VERSION 5.7 ;
BUSBITCHARS "[]" ;
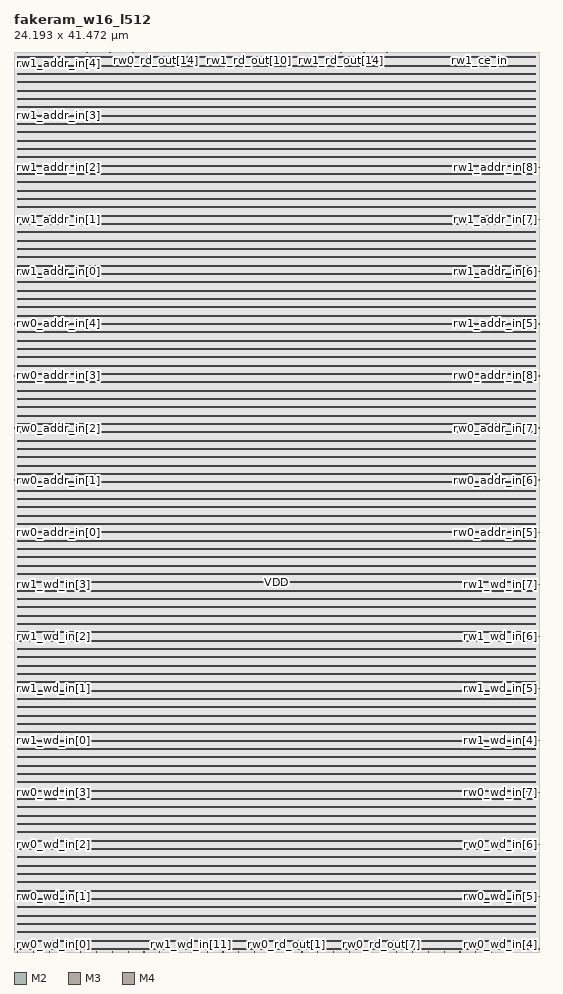
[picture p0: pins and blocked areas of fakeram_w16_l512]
MACRO fakeram_w16_l512
  FOREIGN fakeram_w16_l512 0 0 ;
  SYMMETRY X Y R90 ;
  SIZE 24.193 BY 41.472 ;
  CLASS BLOCK ;
  PIN rw0_wd_in[0]
    DIRECTION INPUT ;
    USE SIGNAL ;
    SHAPE ABUTMENT ;
    PORT
      LAYER M2 ;
      RECT 0.000 0.138 0.036 0.150 ;
    END
  END rw0_wd_in[0]
  PIN rw0_wd_in[1]
    DIRECTION INPUT ;
    USE SIGNAL ;
    SHAPE ABUTMENT ;
    PORT
      LAYER M2 ;
      RECT 0.000 2.538 0.036 2.550 ;
    END
  END rw0_wd_in[1]
  PIN rw0_wd_in[2]
    DIRECTION INPUT ;
    USE SIGNAL ;
    SHAPE ABUTMENT ;
    PORT
      LAYER M2 ;
      RECT 0.000 4.938 0.036 4.950 ;
    END
  END rw0_wd_in[2]
  PIN rw0_wd_in[3]
    DIRECTION INPUT ;
    USE SIGNAL ;
    SHAPE ABUTMENT ;
    PORT
      LAYER M2 ;
      RECT 0.000 7.338 0.036 7.350 ;
    END
  END rw0_wd_in[3]
  PIN rw0_wd_in[4]
    DIRECTION INPUT ;
    USE SIGNAL ;
    SHAPE ABUTMENT ;
    PORT
      LAYER M2 ;
      RECT 24.157 0.138 24.193 0.150 ;
    END
  END rw0_wd_in[4]
  PIN rw0_wd_in[5]
    DIRECTION INPUT ;
    USE SIGNAL ;
    SHAPE ABUTMENT ;
    PORT
      LAYER M2 ;
      RECT 24.157 2.538 24.193 2.550 ;
    END
  END rw0_wd_in[5]
  PIN rw0_wd_in[6]
    DIRECTION INPUT ;
    USE SIGNAL ;
    SHAPE ABUTMENT ;
    PORT
      LAYER M2 ;
      RECT 24.157 4.938 24.193 4.950 ;
    END
  END rw0_wd_in[6]
  PIN rw0_wd_in[7]
    DIRECTION INPUT ;
    USE SIGNAL ;
    SHAPE ABUTMENT ;
    PORT
      LAYER M2 ;
      RECT 24.157 7.338 24.193 7.350 ;
    END
  END rw0_wd_in[7]
  PIN rw0_wd_in[8]
    DIRECTION INPUT ;
    USE SIGNAL ;
    SHAPE ABUTMENT ;
    PORT
      LAYER M3 ;
      RECT 0.161 0.000 0.175 0.042 ;
    END
  END rw0_wd_in[8]
  PIN rw0_wd_in[9]
    DIRECTION INPUT ;
    USE SIGNAL ;
    SHAPE ABUTMENT ;
    PORT
      LAYER M3 ;
      RECT 0.889 0.000 0.903 0.042 ;
    END
  END rw0_wd_in[9]
  PIN rw0_wd_in[10]
    DIRECTION INPUT ;
    USE SIGNAL ;
    SHAPE ABUTMENT ;
    PORT
      LAYER M3 ;
      RECT 1.617 0.000 1.631 0.042 ;
    END
  END rw0_wd_in[10]
  PIN rw0_wd_in[11]
    DIRECTION INPUT ;
    USE SIGNAL ;
    SHAPE ABUTMENT ;
    PORT
      LAYER M3 ;
      RECT 2.345 0.000 2.359 0.042 ;
    END
  END rw0_wd_in[11]
  PIN rw0_wd_in[12]
    DIRECTION INPUT ;
    USE SIGNAL ;
    SHAPE ABUTMENT ;
    PORT
      LAYER M3 ;
      RECT 3.073 0.000 3.087 0.042 ;
    END
  END rw0_wd_in[12]
  PIN rw0_wd_in[13]
    DIRECTION INPUT ;
    USE SIGNAL ;
    SHAPE ABUTMENT ;
    PORT
      LAYER M3 ;
      RECT 3.801 0.000 3.815 0.042 ;
    END
  END rw0_wd_in[13]
  PIN rw0_wd_in[14]
    DIRECTION INPUT ;
    USE SIGNAL ;
    SHAPE ABUTMENT ;
    PORT
      LAYER M3 ;
      RECT 4.529 0.000 4.543 0.042 ;
    END
  END rw0_wd_in[14]
  PIN rw0_wd_in[15]
    DIRECTION INPUT ;
    USE SIGNAL ;
    SHAPE ABUTMENT ;
    PORT
      LAYER M3 ;
      RECT 5.257 0.000 5.271 0.042 ;
    END
  END rw0_wd_in[15]
  PIN rw1_wd_in[0]
    DIRECTION INPUT ;
    USE SIGNAL ;
    SHAPE ABUTMENT ;
    PORT
      LAYER M2 ;
      RECT 0.000 9.738 0.036 9.750 ;
    END
  END rw1_wd_in[0]
  PIN rw1_wd_in[1]
    DIRECTION INPUT ;
    USE SIGNAL ;
    SHAPE ABUTMENT ;
    PORT
      LAYER M2 ;
      RECT 0.000 12.138 0.036 12.150 ;
    END
  END rw1_wd_in[1]
  PIN rw1_wd_in[2]
    DIRECTION INPUT ;
    USE SIGNAL ;
    SHAPE ABUTMENT ;
    PORT
      LAYER M2 ;
      RECT 0.000 14.538 0.036 14.550 ;
    END
  END rw1_wd_in[2]
  PIN rw1_wd_in[3]
    DIRECTION INPUT ;
    USE SIGNAL ;
    SHAPE ABUTMENT ;
    PORT
      LAYER M2 ;
      RECT 0.000 16.938 0.036 16.950 ;
    END
  END rw1_wd_in[3]
  PIN rw1_wd_in[4]
    DIRECTION INPUT ;
    USE SIGNAL ;
    SHAPE ABUTMENT ;
    PORT
      LAYER M2 ;
      RECT 24.157 9.738 24.193 9.750 ;
    END
  END rw1_wd_in[4]
  PIN rw1_wd_in[5]
    DIRECTION INPUT ;
    USE SIGNAL ;
    SHAPE ABUTMENT ;
    PORT
      LAYER M2 ;
      RECT 24.157 12.138 24.193 12.150 ;
    END
  END rw1_wd_in[5]
  PIN rw1_wd_in[6]
    DIRECTION INPUT ;
    USE SIGNAL ;
    SHAPE ABUTMENT ;
    PORT
      LAYER M2 ;
      RECT 24.157 14.538 24.193 14.550 ;
    END
  END rw1_wd_in[6]
  PIN rw1_wd_in[7]
    DIRECTION INPUT ;
    USE SIGNAL ;
    SHAPE ABUTMENT ;
    PORT
      LAYER M2 ;
      RECT 24.157 16.938 24.193 16.950 ;
    END
  END rw1_wd_in[7]
  PIN rw1_wd_in[8]
    DIRECTION INPUT ;
    USE SIGNAL ;
    SHAPE ABUTMENT ;
    PORT
      LAYER M3 ;
      RECT 5.985 0.000 5.999 0.042 ;
    END
  END rw1_wd_in[8]
  PIN rw1_wd_in[9]
    DIRECTION INPUT ;
    USE SIGNAL ;
    SHAPE ABUTMENT ;
    PORT
      LAYER M3 ;
      RECT 6.713 0.000 6.727 0.042 ;
    END
  END rw1_wd_in[9]
  PIN rw1_wd_in[10]
    DIRECTION INPUT ;
    USE SIGNAL ;
    SHAPE ABUTMENT ;
    PORT
      LAYER M3 ;
      RECT 7.441 0.000 7.455 0.042 ;
    END
  END rw1_wd_in[10]
  PIN rw1_wd_in[11]
    DIRECTION INPUT ;
    USE SIGNAL ;
    SHAPE ABUTMENT ;
    PORT
      LAYER M3 ;
      RECT 8.169 0.000 8.183 0.042 ;
    END
  END rw1_wd_in[11]
  PIN rw1_wd_in[12]
    DIRECTION INPUT ;
    USE SIGNAL ;
    SHAPE ABUTMENT ;
    PORT
      LAYER M3 ;
      RECT 8.897 0.000 8.911 0.042 ;
    END
  END rw1_wd_in[12]
  PIN rw1_wd_in[13]
    DIRECTION INPUT ;
    USE SIGNAL ;
    SHAPE ABUTMENT ;
    PORT
      LAYER M3 ;
      RECT 9.625 0.000 9.639 0.042 ;
    END
  END rw1_wd_in[13]
  PIN rw1_wd_in[14]
    DIRECTION INPUT ;
    USE SIGNAL ;
    SHAPE ABUTMENT ;
    PORT
      LAYER M3 ;
      RECT 10.353 0.000 10.367 0.042 ;
    END
  END rw1_wd_in[14]
  PIN rw1_wd_in[15]
    DIRECTION INPUT ;
    USE SIGNAL ;
    SHAPE ABUTMENT ;
    PORT
      LAYER M3 ;
      RECT 11.081 0.000 11.095 0.042 ;
    END
  END rw1_wd_in[15]
  PIN rw0_rd_out[0]
    DIRECTION OUTPUT ;
    USE SIGNAL ;
    SHAPE ABUTMENT ;
    PORT
      LAYER M3 ;
      RECT 11.809 0.000 11.823 0.042 ;
    END
  END rw0_rd_out[0]
  PIN rw0_rd_out[1]
    DIRECTION OUTPUT ;
    USE SIGNAL ;
    SHAPE ABUTMENT ;
    PORT
      LAYER M3 ;
      RECT 12.537 0.000 12.551 0.042 ;
    END
  END rw0_rd_out[1]
  PIN rw0_rd_out[2]
    DIRECTION OUTPUT ;
    USE SIGNAL ;
    SHAPE ABUTMENT ;
    PORT
      LAYER M3 ;
      RECT 13.265 0.000 13.279 0.042 ;
    END
  END rw0_rd_out[2]
  PIN rw0_rd_out[3]
    DIRECTION OUTPUT ;
    USE SIGNAL ;
    SHAPE ABUTMENT ;
    PORT
      LAYER M3 ;
      RECT 13.993 0.000 14.007 0.042 ;
    END
  END rw0_rd_out[3]
  PIN rw0_rd_out[4]
    DIRECTION OUTPUT ;
    USE SIGNAL ;
    SHAPE ABUTMENT ;
    PORT
      LAYER M3 ;
      RECT 14.721 0.000 14.735 0.042 ;
    END
  END rw0_rd_out[4]
  PIN rw0_rd_out[5]
    DIRECTION OUTPUT ;
    USE SIGNAL ;
    SHAPE ABUTMENT ;
    PORT
      LAYER M3 ;
      RECT 15.449 0.000 15.463 0.042 ;
    END
  END rw0_rd_out[5]
  PIN rw0_rd_out[6]
    DIRECTION OUTPUT ;
    USE SIGNAL ;
    SHAPE ABUTMENT ;
    PORT
      LAYER M3 ;
      RECT 16.177 0.000 16.191 0.042 ;
    END
  END rw0_rd_out[6]
  PIN rw0_rd_out[7]
    DIRECTION OUTPUT ;
    USE SIGNAL ;
    SHAPE ABUTMENT ;
    PORT
      LAYER M3 ;
      RECT 16.905 0.000 16.919 0.042 ;
    END
  END rw0_rd_out[7]
  PIN rw0_rd_out[8]
    DIRECTION OUTPUT ;
    USE SIGNAL ;
    SHAPE ABUTMENT ;
    PORT
      LAYER M3 ;
      RECT 0.161 41.430 0.175 41.472 ;
    END
  END rw0_rd_out[8]
  PIN rw0_rd_out[9]
    DIRECTION OUTPUT ;
    USE SIGNAL ;
    SHAPE ABUTMENT ;
    PORT
      LAYER M3 ;
      RECT 1.225 41.430 1.239 41.472 ;
    END
  END rw0_rd_out[9]
  PIN rw0_rd_out[10]
    DIRECTION OUTPUT ;
    USE SIGNAL ;
    SHAPE ABUTMENT ;
    PORT
      LAYER M3 ;
      RECT 2.289 41.430 2.303 41.472 ;
    END
  END rw0_rd_out[10]
  PIN rw0_rd_out[11]
    DIRECTION OUTPUT ;
    USE SIGNAL ;
    SHAPE ABUTMENT ;
    PORT
      LAYER M3 ;
      RECT 3.353 41.430 3.367 41.472 ;
    END
  END rw0_rd_out[11]
  PIN rw0_rd_out[12]
    DIRECTION OUTPUT ;
    USE SIGNAL ;
    SHAPE ABUTMENT ;
    PORT
      LAYER M3 ;
      RECT 4.417 41.430 4.431 41.472 ;
    END
  END rw0_rd_out[12]
  PIN rw0_rd_out[13]
    DIRECTION OUTPUT ;
    USE SIGNAL ;
    SHAPE ABUTMENT ;
    PORT
      LAYER M3 ;
      RECT 5.481 41.430 5.495 41.472 ;
    END
  END rw0_rd_out[13]
  PIN rw0_rd_out[14]
    DIRECTION OUTPUT ;
    USE SIGNAL ;
    SHAPE ABUTMENT ;
    PORT
      LAYER M3 ;
      RECT 6.545 41.430 6.559 41.472 ;
    END
  END rw0_rd_out[14]
  PIN rw0_rd_out[15]
    DIRECTION OUTPUT ;
    USE SIGNAL ;
    SHAPE ABUTMENT ;
    PORT
      LAYER M3 ;
      RECT 7.609 41.430 7.623 41.472 ;
    END
  END rw0_rd_out[15]
  PIN rw1_rd_out[0]
    DIRECTION OUTPUT ;
    USE SIGNAL ;
    SHAPE ABUTMENT ;
    PORT
      LAYER M3 ;
      RECT 17.633 0.000 17.647 0.042 ;
    END
  END rw1_rd_out[0]
  PIN rw1_rd_out[1]
    DIRECTION OUTPUT ;
    USE SIGNAL ;
    SHAPE ABUTMENT ;
    PORT
      LAYER M3 ;
      RECT 18.361 0.000 18.375 0.042 ;
    END
  END rw1_rd_out[1]
  PIN rw1_rd_out[2]
    DIRECTION OUTPUT ;
    USE SIGNAL ;
    SHAPE ABUTMENT ;
    PORT
      LAYER M3 ;
      RECT 19.089 0.000 19.103 0.042 ;
    END
  END rw1_rd_out[2]
  PIN rw1_rd_out[3]
    DIRECTION OUTPUT ;
    USE SIGNAL ;
    SHAPE ABUTMENT ;
    PORT
      LAYER M3 ;
      RECT 19.817 0.000 19.831 0.042 ;
    END
  END rw1_rd_out[3]
  PIN rw1_rd_out[4]
    DIRECTION OUTPUT ;
    USE SIGNAL ;
    SHAPE ABUTMENT ;
    PORT
      LAYER M3 ;
      RECT 20.545 0.000 20.559 0.042 ;
    END
  END rw1_rd_out[4]
  PIN rw1_rd_out[5]
    DIRECTION OUTPUT ;
    USE SIGNAL ;
    SHAPE ABUTMENT ;
    PORT
      LAYER M3 ;
      RECT 21.273 0.000 21.287 0.042 ;
    END
  END rw1_rd_out[5]
  PIN rw1_rd_out[6]
    DIRECTION OUTPUT ;
    USE SIGNAL ;
    SHAPE ABUTMENT ;
    PORT
      LAYER M3 ;
      RECT 22.001 0.000 22.015 0.042 ;
    END
  END rw1_rd_out[6]
  PIN rw1_rd_out[7]
    DIRECTION OUTPUT ;
    USE SIGNAL ;
    SHAPE ABUTMENT ;
    PORT
      LAYER M3 ;
      RECT 22.729 0.000 22.743 0.042 ;
    END
  END rw1_rd_out[7]
  PIN rw1_rd_out[8]
    DIRECTION OUTPUT ;
    USE SIGNAL ;
    SHAPE ABUTMENT ;
    PORT
      LAYER M3 ;
      RECT 8.673 41.430 8.687 41.472 ;
    END
  END rw1_rd_out[8]
  PIN rw1_rd_out[9]
    DIRECTION OUTPUT ;
    USE SIGNAL ;
    SHAPE ABUTMENT ;
    PORT
      LAYER M3 ;
      RECT 9.737 41.430 9.751 41.472 ;
    END
  END rw1_rd_out[9]
  PIN rw1_rd_out[10]
    DIRECTION OUTPUT ;
    USE SIGNAL ;
    SHAPE ABUTMENT ;
    PORT
      LAYER M3 ;
      RECT 10.801 41.430 10.815 41.472 ;
    END
  END rw1_rd_out[10]
  PIN rw1_rd_out[11]
    DIRECTION OUTPUT ;
    USE SIGNAL ;
    SHAPE ABUTMENT ;
    PORT
      LAYER M3 ;
      RECT 11.865 41.430 11.879 41.472 ;
    END
  END rw1_rd_out[11]
  PIN rw1_rd_out[12]
    DIRECTION OUTPUT ;
    USE SIGNAL ;
    SHAPE ABUTMENT ;
    PORT
      LAYER M3 ;
      RECT 12.929 41.430 12.943 41.472 ;
    END
  END rw1_rd_out[12]
  PIN rw1_rd_out[13]
    DIRECTION OUTPUT ;
    USE SIGNAL ;
    SHAPE ABUTMENT ;
    PORT
      LAYER M3 ;
      RECT 13.993 41.430 14.007 41.472 ;
    END
  END rw1_rd_out[13]
  PIN rw1_rd_out[14]
    DIRECTION OUTPUT ;
    USE SIGNAL ;
    SHAPE ABUTMENT ;
    PORT
      LAYER M3 ;
      RECT 15.057 41.430 15.071 41.472 ;
    END
  END rw1_rd_out[14]
  PIN rw1_rd_out[15]
    DIRECTION OUTPUT ;
    USE SIGNAL ;
    SHAPE ABUTMENT ;
    PORT
      LAYER M3 ;
      RECT 16.121 41.430 16.135 41.472 ;
    END
  END rw1_rd_out[15]
  PIN rw0_addr_in[0]
    DIRECTION INPUT ;
    USE SIGNAL ;
    SHAPE ABUTMENT ;
    PORT
      LAYER M2 ;
      RECT 0.000 19.338 0.036 19.350 ;
    END
  END rw0_addr_in[0]
  PIN rw0_addr_in[1]
    DIRECTION INPUT ;
    USE SIGNAL ;
    SHAPE ABUTMENT ;
    PORT
      LAYER M2 ;
      RECT 0.000 21.738 0.036 21.750 ;
    END
  END rw0_addr_in[1]
  PIN rw0_addr_in[2]
    DIRECTION INPUT ;
    USE SIGNAL ;
    SHAPE ABUTMENT ;
    PORT
      LAYER M2 ;
      RECT 0.000 24.138 0.036 24.150 ;
    END
  END rw0_addr_in[2]
  PIN rw0_addr_in[3]
    DIRECTION INPUT ;
    USE SIGNAL ;
    SHAPE ABUTMENT ;
    PORT
      LAYER M2 ;
      RECT 0.000 26.538 0.036 26.550 ;
    END
  END rw0_addr_in[3]
  PIN rw0_addr_in[4]
    DIRECTION INPUT ;
    USE SIGNAL ;
    SHAPE ABUTMENT ;
    PORT
      LAYER M2 ;
      RECT 0.000 28.938 0.036 28.950 ;
    END
  END rw0_addr_in[4]
  PIN rw0_addr_in[5]
    DIRECTION INPUT ;
    USE SIGNAL ;
    SHAPE ABUTMENT ;
    PORT
      LAYER M2 ;
      RECT 24.157 19.338 24.193 19.350 ;
    END
  END rw0_addr_in[5]
  PIN rw0_addr_in[6]
    DIRECTION INPUT ;
    USE SIGNAL ;
    SHAPE ABUTMENT ;
    PORT
      LAYER M2 ;
      RECT 24.157 21.738 24.193 21.750 ;
    END
  END rw0_addr_in[6]
  PIN rw0_addr_in[7]
    DIRECTION INPUT ;
    USE SIGNAL ;
    SHAPE ABUTMENT ;
    PORT
      LAYER M2 ;
      RECT 24.157 24.138 24.193 24.150 ;
    END
  END rw0_addr_in[7]
  PIN rw0_addr_in[8]
    DIRECTION INPUT ;
    USE SIGNAL ;
    SHAPE ABUTMENT ;
    PORT
      LAYER M2 ;
      RECT 24.157 26.538 24.193 26.550 ;
    END
  END rw0_addr_in[8]
  PIN rw1_addr_in[0]
    DIRECTION INPUT ;
    USE SIGNAL ;
    SHAPE ABUTMENT ;
    PORT
      LAYER M2 ;
      RECT 0.000 31.338 0.036 31.350 ;
    END
  END rw1_addr_in[0]
  PIN rw1_addr_in[1]
    DIRECTION INPUT ;
    USE SIGNAL ;
    SHAPE ABUTMENT ;
    PORT
      LAYER M2 ;
      RECT 0.000 33.738 0.036 33.750 ;
    END
  END rw1_addr_in[1]
  PIN rw1_addr_in[2]
    DIRECTION INPUT ;
    USE SIGNAL ;
    SHAPE ABUTMENT ;
    PORT
      LAYER M2 ;
      RECT 0.000 36.138 0.036 36.150 ;
    END
  END rw1_addr_in[2]
  PIN rw1_addr_in[3]
    DIRECTION INPUT ;
    USE SIGNAL ;
    SHAPE ABUTMENT ;
    PORT
      LAYER M2 ;
      RECT 0.000 38.538 0.036 38.550 ;
    END
  END rw1_addr_in[3]
  PIN rw1_addr_in[4]
    DIRECTION INPUT ;
    USE SIGNAL ;
    SHAPE ABUTMENT ;
    PORT
      LAYER M2 ;
      RECT 0.000 40.938 0.036 40.950 ;
    END
  END rw1_addr_in[4]
  PIN rw1_addr_in[5]
    DIRECTION INPUT ;
    USE SIGNAL ;
    SHAPE ABUTMENT ;
    PORT
      LAYER M2 ;
      RECT 24.157 28.938 24.193 28.950 ;
    END
  END rw1_addr_in[5]
  PIN rw1_addr_in[6]
    DIRECTION INPUT ;
    USE SIGNAL ;
    SHAPE ABUTMENT ;
    PORT
      LAYER M2 ;
      RECT 24.157 31.338 24.193 31.350 ;
    END
  END rw1_addr_in[6]
  PIN rw1_addr_in[7]
    DIRECTION INPUT ;
    USE SIGNAL ;
    SHAPE ABUTMENT ;
    PORT
      LAYER M2 ;
      RECT 24.157 33.738 24.193 33.750 ;
    END
  END rw1_addr_in[7]
  PIN rw1_addr_in[8]
    DIRECTION INPUT ;
    USE SIGNAL ;
    SHAPE ABUTMENT ;
    PORT
      LAYER M2 ;
      RECT 24.157 36.138 24.193 36.150 ;
    END
  END rw1_addr_in[8]
  PIN rw0_we_in
    DIRECTION INPUT ;
    USE SIGNAL ;
    SHAPE ABUTMENT ;
    PORT
      LAYER M3 ;
      RECT 17.185 41.430 17.199 41.472 ;
    END
  END rw0_we_in
  PIN rw0_ce_in
    DIRECTION INPUT ;
    USE SIGNAL ;
    SHAPE ABUTMENT ;
    PORT
      LAYER M3 ;
      RECT 18.249 41.430 18.263 41.472 ;
    END
  END rw0_ce_in
  PIN rw0_clk
    DIRECTION INPUT ;
    USE SIGNAL ;
    SHAPE ABUTMENT ;
    PORT
      LAYER M3 ;
      RECT 19.313 41.430 19.327 41.472 ;
    END
  END rw0_clk
  PIN rw1_we_in
    DIRECTION INPUT ;
    USE SIGNAL ;
    SHAPE ABUTMENT ;
    PORT
      LAYER M3 ;
      RECT 20.377 41.430 20.391 41.472 ;
    END
  END rw1_we_in
  PIN rw1_ce_in
    DIRECTION INPUT ;
    USE SIGNAL ;
    SHAPE ABUTMENT ;
    PORT
      LAYER M3 ;
      RECT 21.441 41.430 21.455 41.472 ;
    END
  END rw1_ce_in
  PIN rw1_clk
    DIRECTION INPUT ;
    USE SIGNAL ;
    SHAPE ABUTMENT ;
    PORT
      LAYER M3 ;
      RECT 22.505 41.430 22.519 41.472 ;
    END
  END rw1_clk
  PIN VSS
    DIRECTION INOUT ;
    USE GROUND ;
    PORT
      LAYER M4 ;
      RECT 0.168 0.120 24.025 0.168 ;
      RECT 0.168 0.504 24.025 0.552 ;
      RECT 0.168 0.888 24.025 0.936 ;
      RECT 0.168 1.272 24.025 1.320 ;
      RECT 0.168 1.656 24.025 1.704 ;
      RECT 0.168 2.040 24.025 2.088 ;
      RECT 0.168 2.424 24.025 2.472 ;
      RECT 0.168 2.808 24.025 2.856 ;
      RECT 0.168 3.192 24.025 3.240 ;
      RECT 0.168 3.576 24.025 3.624 ;
      RECT 0.168 3.960 24.025 4.008 ;
      RECT 0.168 4.344 24.025 4.392 ;
      RECT 0.168 4.728 24.025 4.776 ;
      RECT 0.168 5.112 24.025 5.160 ;
      RECT 0.168 5.496 24.025 5.544 ;
      RECT 0.168 5.880 24.025 5.928 ;
      RECT 0.168 6.264 24.025 6.312 ;
      RECT 0.168 6.648 24.025 6.696 ;
      RECT 0.168 7.032 24.025 7.080 ;
      RECT 0.168 7.416 24.025 7.464 ;
      RECT 0.168 7.800 24.025 7.848 ;
      RECT 0.168 8.184 24.025 8.232 ;
      RECT 0.168 8.568 24.025 8.616 ;
      RECT 0.168 8.952 24.025 9.000 ;
      RECT 0.168 9.336 24.025 9.384 ;
      RECT 0.168 9.720 24.025 9.768 ;
      RECT 0.168 10.104 24.025 10.152 ;
      RECT 0.168 10.488 24.025 10.536 ;
      RECT 0.168 10.872 24.025 10.920 ;
      RECT 0.168 11.256 24.025 11.304 ;
      RECT 0.168 11.640 24.025 11.688 ;
      RECT 0.168 12.024 24.025 12.072 ;
      RECT 0.168 12.408 24.025 12.456 ;
      RECT 0.168 12.792 24.025 12.840 ;
      RECT 0.168 13.176 24.025 13.224 ;
      RECT 0.168 13.560 24.025 13.608 ;
      RECT 0.168 13.944 24.025 13.992 ;
      RECT 0.168 14.328 24.025 14.376 ;
      RECT 0.168 14.712 24.025 14.760 ;
      RECT 0.168 15.096 24.025 15.144 ;
      RECT 0.168 15.480 24.025 15.528 ;
      RECT 0.168 15.864 24.025 15.912 ;
      RECT 0.168 16.248 24.025 16.296 ;
      RECT 0.168 16.632 24.025 16.680 ;
      RECT 0.168 17.016 24.025 17.064 ;
      RECT 0.168 17.400 24.025 17.448 ;
      RECT 0.168 17.784 24.025 17.832 ;
      RECT 0.168 18.168 24.025 18.216 ;
      RECT 0.168 18.552 24.025 18.600 ;
      RECT 0.168 18.936 24.025 18.984 ;
      RECT 0.168 19.320 24.025 19.368 ;
      RECT 0.168 19.704 24.025 19.752 ;
      RECT 0.168 20.088 24.025 20.136 ;
      RECT 0.168 20.472 24.025 20.520 ;
      RECT 0.168 20.856 24.025 20.904 ;
      RECT 0.168 21.240 24.025 21.288 ;
      RECT 0.168 21.624 24.025 21.672 ;
      RECT 0.168 22.008 24.025 22.056 ;
      RECT 0.168 22.392 24.025 22.440 ;
      RECT 0.168 22.776 24.025 22.824 ;
      RECT 0.168 23.160 24.025 23.208 ;
      RECT 0.168 23.544 24.025 23.592 ;
      RECT 0.168 23.928 24.025 23.976 ;
      RECT 0.168 24.312 24.025 24.360 ;
      RECT 0.168 24.696 24.025 24.744 ;
      RECT 0.168 25.080 24.025 25.128 ;
      RECT 0.168 25.464 24.025 25.512 ;
      RECT 0.168 25.848 24.025 25.896 ;
      RECT 0.168 26.232 24.025 26.280 ;
      RECT 0.168 26.616 24.025 26.664 ;
      RECT 0.168 27.000 24.025 27.048 ;
      RECT 0.168 27.384 24.025 27.432 ;
      RECT 0.168 27.768 24.025 27.816 ;
      RECT 0.168 28.152 24.025 28.200 ;
      RECT 0.168 28.536 24.025 28.584 ;
      RECT 0.168 28.920 24.025 28.968 ;
      RECT 0.168 29.304 24.025 29.352 ;
      RECT 0.168 29.688 24.025 29.736 ;
      RECT 0.168 30.072 24.025 30.120 ;
      RECT 0.168 30.456 24.025 30.504 ;
      RECT 0.168 30.840 24.025 30.888 ;
      RECT 0.168 31.224 24.025 31.272 ;
      RECT 0.168 31.608 24.025 31.656 ;
      RECT 0.168 31.992 24.025 32.040 ;
      RECT 0.168 32.376 24.025 32.424 ;
      RECT 0.168 32.760 24.025 32.808 ;
      RECT 0.168 33.144 24.025 33.192 ;
      RECT 0.168 33.528 24.025 33.576 ;
      RECT 0.168 33.912 24.025 33.960 ;
      RECT 0.168 34.296 24.025 34.344 ;
      RECT 0.168 34.680 24.025 34.728 ;
      RECT 0.168 35.064 24.025 35.112 ;
      RECT 0.168 35.448 24.025 35.496 ;
      RECT 0.168 35.832 24.025 35.880 ;
      RECT 0.168 36.216 24.025 36.264 ;
      RECT 0.168 36.600 24.025 36.648 ;
      RECT 0.168 36.984 24.025 37.032 ;
      RECT 0.168 37.368 24.025 37.416 ;
      RECT 0.168 37.752 24.025 37.800 ;
      RECT 0.168 38.136 24.025 38.184 ;
      RECT 0.168 38.520 24.025 38.568 ;
      RECT 0.168 38.904 24.025 38.952 ;
      RECT 0.168 39.288 24.025 39.336 ;
      RECT 0.168 39.672 24.025 39.720 ;
      RECT 0.168 40.056 24.025 40.104 ;
      RECT 0.168 40.440 24.025 40.488 ;
      RECT 0.168 40.824 24.025 40.872 ;
      RECT 0.168 41.208 24.025 41.256 ;
    END
  END VSS
  PIN VDD
    DIRECTION INOUT ;
    USE POWER ;
    PORT
      LAYER M4 ;
      RECT 0.168 0.120 24.025 0.168 ;
      RECT 0.168 0.504 24.025 0.552 ;
      RECT 0.168 0.888 24.025 0.936 ;
      RECT 0.168 1.272 24.025 1.320 ;
      RECT 0.168 1.656 24.025 1.704 ;
      RECT 0.168 2.040 24.025 2.088 ;
      RECT 0.168 2.424 24.025 2.472 ;
      RECT 0.168 2.808 24.025 2.856 ;
      RECT 0.168 3.192 24.025 3.240 ;
      RECT 0.168 3.576 24.025 3.624 ;
      RECT 0.168 3.960 24.025 4.008 ;
      RECT 0.168 4.344 24.025 4.392 ;
      RECT 0.168 4.728 24.025 4.776 ;
      RECT 0.168 5.112 24.025 5.160 ;
      RECT 0.168 5.496 24.025 5.544 ;
      RECT 0.168 5.880 24.025 5.928 ;
      RECT 0.168 6.264 24.025 6.312 ;
      RECT 0.168 6.648 24.025 6.696 ;
      RECT 0.168 7.032 24.025 7.080 ;
      RECT 0.168 7.416 24.025 7.464 ;
      RECT 0.168 7.800 24.025 7.848 ;
      RECT 0.168 8.184 24.025 8.232 ;
      RECT 0.168 8.568 24.025 8.616 ;
      RECT 0.168 8.952 24.025 9.000 ;
      RECT 0.168 9.336 24.025 9.384 ;
      RECT 0.168 9.720 24.025 9.768 ;
      RECT 0.168 10.104 24.025 10.152 ;
      RECT 0.168 10.488 24.025 10.536 ;
      RECT 0.168 10.872 24.025 10.920 ;
      RECT 0.168 11.256 24.025 11.304 ;
      RECT 0.168 11.640 24.025 11.688 ;
      RECT 0.168 12.024 24.025 12.072 ;
      RECT 0.168 12.408 24.025 12.456 ;
      RECT 0.168 12.792 24.025 12.840 ;
      RECT 0.168 13.176 24.025 13.224 ;
      RECT 0.168 13.560 24.025 13.608 ;
      RECT 0.168 13.944 24.025 13.992 ;
      RECT 0.168 14.328 24.025 14.376 ;
      RECT 0.168 14.712 24.025 14.760 ;
      RECT 0.168 15.096 24.025 15.144 ;
      RECT 0.168 15.480 24.025 15.528 ;
      RECT 0.168 15.864 24.025 15.912 ;
      RECT 0.168 16.248 24.025 16.296 ;
      RECT 0.168 16.632 24.025 16.680 ;
      RECT 0.168 17.016 24.025 17.064 ;
      RECT 0.168 17.400 24.025 17.448 ;
      RECT 0.168 17.784 24.025 17.832 ;
      RECT 0.168 18.168 24.025 18.216 ;
      RECT 0.168 18.552 24.025 18.600 ;
      RECT 0.168 18.936 24.025 18.984 ;
      RECT 0.168 19.320 24.025 19.368 ;
      RECT 0.168 19.704 24.025 19.752 ;
      RECT 0.168 20.088 24.025 20.136 ;
      RECT 0.168 20.472 24.025 20.520 ;
      RECT 0.168 20.856 24.025 20.904 ;
      RECT 0.168 21.240 24.025 21.288 ;
      RECT 0.168 21.624 24.025 21.672 ;
      RECT 0.168 22.008 24.025 22.056 ;
      RECT 0.168 22.392 24.025 22.440 ;
      RECT 0.168 22.776 24.025 22.824 ;
      RECT 0.168 23.160 24.025 23.208 ;
      RECT 0.168 23.544 24.025 23.592 ;
      RECT 0.168 23.928 24.025 23.976 ;
      RECT 0.168 24.312 24.025 24.360 ;
      RECT 0.168 24.696 24.025 24.744 ;
      RECT 0.168 25.080 24.025 25.128 ;
      RECT 0.168 25.464 24.025 25.512 ;
      RECT 0.168 25.848 24.025 25.896 ;
      RECT 0.168 26.232 24.025 26.280 ;
      RECT 0.168 26.616 24.025 26.664 ;
      RECT 0.168 27.000 24.025 27.048 ;
      RECT 0.168 27.384 24.025 27.432 ;
      RECT 0.168 27.768 24.025 27.816 ;
      RECT 0.168 28.152 24.025 28.200 ;
      RECT 0.168 28.536 24.025 28.584 ;
      RECT 0.168 28.920 24.025 28.968 ;
      RECT 0.168 29.304 24.025 29.352 ;
      RECT 0.168 29.688 24.025 29.736 ;
      RECT 0.168 30.072 24.025 30.120 ;
      RECT 0.168 30.456 24.025 30.504 ;
      RECT 0.168 30.840 24.025 30.888 ;
      RECT 0.168 31.224 24.025 31.272 ;
      RECT 0.168 31.608 24.025 31.656 ;
      RECT 0.168 31.992 24.025 32.040 ;
      RECT 0.168 32.376 24.025 32.424 ;
      RECT 0.168 32.760 24.025 32.808 ;
      RECT 0.168 33.144 24.025 33.192 ;
      RECT 0.168 33.528 24.025 33.576 ;
      RECT 0.168 33.912 24.025 33.960 ;
      RECT 0.168 34.296 24.025 34.344 ;
      RECT 0.168 34.680 24.025 34.728 ;
      RECT 0.168 35.064 24.025 35.112 ;
      RECT 0.168 35.448 24.025 35.496 ;
      RECT 0.168 35.832 24.025 35.880 ;
      RECT 0.168 36.216 24.025 36.264 ;
      RECT 0.168 36.600 24.025 36.648 ;
      RECT 0.168 36.984 24.025 37.032 ;
      RECT 0.168 37.368 24.025 37.416 ;
      RECT 0.168 37.752 24.025 37.800 ;
      RECT 0.168 38.136 24.025 38.184 ;
      RECT 0.168 38.520 24.025 38.568 ;
      RECT 0.168 38.904 24.025 38.952 ;
      RECT 0.168 39.288 24.025 39.336 ;
      RECT 0.168 39.672 24.025 39.720 ;
      RECT 0.168 40.056 24.025 40.104 ;
      RECT 0.168 40.440 24.025 40.488 ;
      RECT 0.168 40.824 24.025 40.872 ;
      RECT 0.168 41.208 24.025 41.256 ;
    END
  END VDD
  OBS
    LAYER M1 ;
    RECT 0 0 24.193 41.472 ;
    LAYER M2 ;
    RECT 0 0 24.193 41.472 ;
    LAYER M3 ;
    RECT 0 0 24.193 41.472 ;
    LAYER M4 ;
    RECT 0 0 24.193 41.472 ;
  END
END fakeram_w16_l512

END LIBRARY
